VERSION 5.7 ;
  NOWIREEXTENSIONATPIN ON ;
  DIVIDERCHAR "/" ;
  BUSBITCHARS "[]" ;
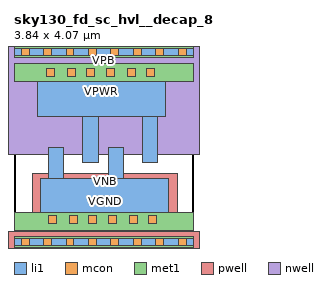
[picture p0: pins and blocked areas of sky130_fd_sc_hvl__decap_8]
MACRO sky130_fd_sc_hvl__decap_8
  CLASS BLOCK ;
  FOREIGN sky130_fd_sc_hvl__decap_8 ;
  ORIGIN 0.000 0.000 ;
  SIZE 3.840 BY 4.070 ;
  PIN VGND
    USE GROUND ;
    PORT
      LAYER li1 ;
        RECT 0.735 1.360 1.065 2.025 ;
        RECT 2.015 1.360 2.345 2.025 ;
        RECT 0.575 0.360 3.305 1.360 ;
      LAYER mcon ;
        RECT 0.745 0.390 0.915 0.560 ;
        RECT 1.185 0.390 1.355 0.560 ;
        RECT 1.600 0.390 1.770 0.560 ;
        RECT 2.025 0.390 2.195 0.560 ;
        RECT 2.465 0.390 2.635 0.560 ;
        RECT 2.880 0.390 3.050 0.560 ;
      LAYER met1 ;
        RECT 0.000 0.255 3.840 0.625 ;
    END
  END VGND
  PIN VNB
    ANTENNADIFFAREA 0.652800 ;
    PORT
      LAYER pwell ;
        RECT 0.405 0.215 3.495 1.470 ;
        RECT -0.130 -0.215 3.970 0.215 ;
      LAYER li1 ;
        RECT 0.000 -0.085 3.840 0.085 ;
      LAYER mcon ;
        RECT 0.155 -0.085 0.325 0.085 ;
        RECT 0.635 -0.085 0.805 0.085 ;
        RECT 1.115 -0.085 1.285 0.085 ;
        RECT 1.595 -0.085 1.765 0.085 ;
        RECT 2.075 -0.085 2.245 0.085 ;
        RECT 2.555 -0.085 2.725 0.085 ;
        RECT 3.035 -0.085 3.205 0.085 ;
        RECT 3.515 -0.085 3.685 0.085 ;
      LAYER met1 ;
        RECT 0.000 -0.115 3.840 0.115 ;
    END
  END VNB
  PIN VPB
    ANTENNADIFFAREA 0.652800 ;
    PORT
      LAYER nwell ;
        RECT -0.330 1.885 4.170 4.485 ;
      LAYER li1 ;
        RECT 0.000 3.985 3.840 4.155 ;
      LAYER mcon ;
        RECT 0.155 3.985 0.325 4.155 ;
        RECT 0.635 3.985 0.805 4.155 ;
        RECT 1.115 3.985 1.285 4.155 ;
        RECT 1.595 3.985 1.765 4.155 ;
        RECT 2.075 3.985 2.245 4.155 ;
        RECT 2.555 3.985 2.725 4.155 ;
        RECT 3.035 3.985 3.205 4.155 ;
        RECT 3.515 3.985 3.685 4.155 ;
      LAYER met1 ;
        RECT 0.000 3.955 3.840 4.185 ;
    END
  END VPB
  PIN VPWR
    USE POWER ;
    PORT
      LAYER li1 ;
        RECT 0.500 2.680 3.240 3.750 ;
        RECT 1.470 1.695 1.800 2.680 ;
        RECT 2.750 1.695 3.080 2.680 ;
      LAYER mcon ;
        RECT 0.705 3.555 0.875 3.725 ;
        RECT 1.145 3.555 1.315 3.725 ;
        RECT 1.560 3.555 1.730 3.725 ;
        RECT 1.985 3.555 2.155 3.725 ;
        RECT 2.425 3.555 2.595 3.725 ;
        RECT 2.840 3.555 3.010 3.725 ;
      LAYER met1 ;
        RECT 0.000 3.445 3.840 3.815 ;
    END
  END VPWR
END sky130_fd_sc_hvl__decap_8
END LIBRARY

